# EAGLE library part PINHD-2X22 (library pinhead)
PIN HEADER

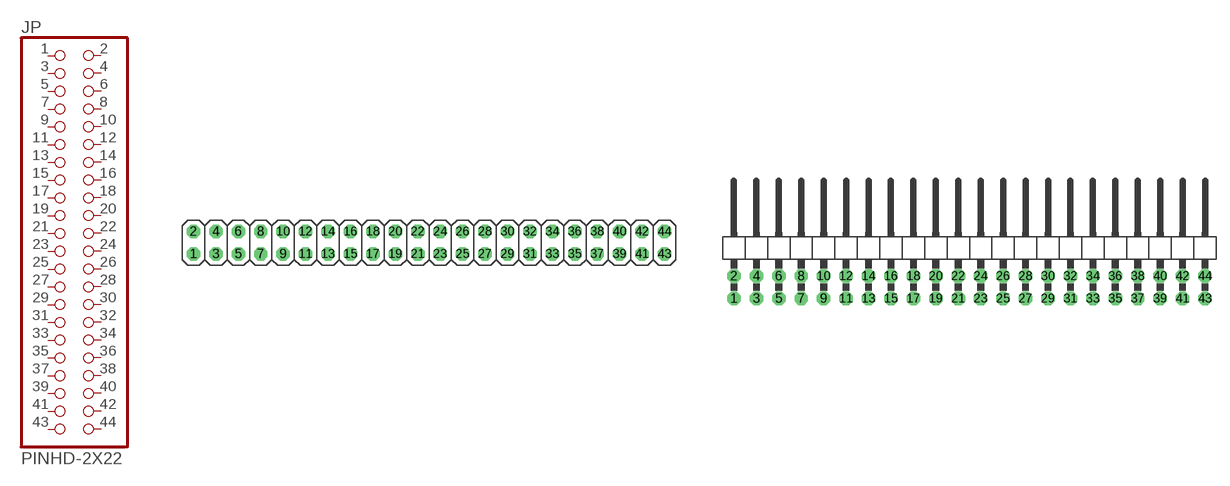
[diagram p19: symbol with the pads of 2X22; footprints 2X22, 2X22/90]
Designator prefix JP

## PINHD-2X22  [2X22]
1  1  pas
2  2  pas
3  3  pas
4  4  pas
5  5  pas
6  6  pas
7  7  pas
8  8  pas
9  9  pas
10  10  pas
11  11  pas
12  12  pas
13  13  pas
14  14  pas
15  15  pas
16  16  pas
17  17  pas
18  18  pas
19  19  pas
20  20  pas
21  21  pas
22  22  pas
23  23  pas
24  24  pas
25  25  pas
26  26  pas
27  27  pas
28  28  pas
29  29  pas
30  30  pas
31  31  pas
32  32  pas
33  33  pas
34  34  pas
35  35  pas
36  36  pas
37  37  pas
38  38  pas
39  39  pas
40  40  pas
41  41  pas
42  42  pas
43  43  pas
44  44  pas

## PINHD-2X22/90  [2X22/90]
1  1  pas
2  2  pas
3  3  pas
4  4  pas
5  5  pas
6  6  pas
7  7  pas
8  8  pas
9  9  pas
10  10  pas
11  11  pas
12  12  pas
13  13  pas
14  14  pas
15  15  pas
16  16  pas
17  17  pas
18  18  pas
19  19  pas
20  20  pas
21  21  pas
22  22  pas
23  23  pas
24  24  pas
25  25  pas
26  26  pas
27  27  pas
28  28  pas
29  29  pas
30  30  pas
31  31  pas
32  32  pas
33  33  pas
34  34  pas
35  35  pas
36  36  pas
37  37  pas
38  38  pas
39  39  pas
40  40  pas
41  42  pas
42  41  pas
43  44  pas
44  43  pas

## Footprint 2X22 (pad centres in mm)
PIN HEADER
drill 1.016 octagon: 1 -25.4,-1.27; 2 -25.4,1.27; 3 -22.86,-1.27; 4 -22.86,1.27; 5 -20.32,-1.27; 6 -20.32,1.27; 7 -17.78,-1.27; 8 -17.78,1.27; 9 -15.24,-1.27; 10 -15.24,1.27; 11 -12.7,-1.27; 12 -12.7,1.27; 13 -10.16,-1.27; 14 -10.16,1.27; 15 -7.62,-1.27; 16 -7.62,1.27; 17 -5.08,-1.27; 18 -5.08,1.27; 19 -2.54,-1.27; 20 -2.54,1.27; 21 0,-1.27; 22 0,1.27; 23 2.54,-1.27; 24 2.54,1.27; 25 5.08,-1.27; 26 5.08,1.27; 27 7.62,-1.27; 28 7.62,1.27; 29 10.16,-1.27; 30 10.16,1.27; 31 12.7,-1.27; 32 12.7,1.27; 33 15.24,-1.27; 34 15.24,1.27; 35 17.78,-1.27; 36 17.78,1.27; 37 20.32,-1.27; 38 20.32,1.27; 39 22.86,-1.27; 40 22.86,1.27; 41 25.4,-1.27; 42 25.4,1.27; 43 27.94,-1.27; 44 27.94,1.27

## Footprint 2X22/90 (pad centres in mm)
PIN HEADER
drill 1.016 octagon: 1 -26.67,-6.35; 2 -26.67,-3.81; 3 -24.13,-6.35; 4 -24.13,-3.81; 5 -21.59,-6.35; 6 -21.59,-3.81; 7 -19.05,-6.35; 8 -19.05,-3.81; 9 -16.51,-6.35; 10 -16.51,-3.81; 11 -13.97,-6.35; 12 -13.97,-3.81; 13 -11.43,-6.35; 14 -11.43,-3.81; 15 -8.89,-6.35; 16 -8.89,-3.81; 17 -6.35,-6.35; 18 -6.35,-3.81; 19 -3.81,-6.35; 20 -3.81,-3.81; 21 -1.27,-6.35; 22 -1.27,-3.81; 23 1.27,-6.35; 24 1.27,-3.81; 25 3.81,-6.35; 26 3.81,-3.81; 27 6.35,-6.35; 28 6.35,-3.81; 29 8.89,-6.35; 30 8.89,-3.81; 31 11.43,-6.35; 32 11.43,-3.81; 33 13.97,-6.35; 34 13.97,-3.81; 35 16.51,-6.35; 36 16.51,-3.81; 37 19.05,-6.35; 38 19.05,-3.81; 39 21.59,-6.35; 40 21.59,-3.81; 41 24.13,-6.35; 42 24.13,-3.81; 43 26.67,-6.35; 44 26.67,-3.81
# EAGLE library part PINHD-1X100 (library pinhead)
PIN HEADER 100 pol. Grid 2.54mm

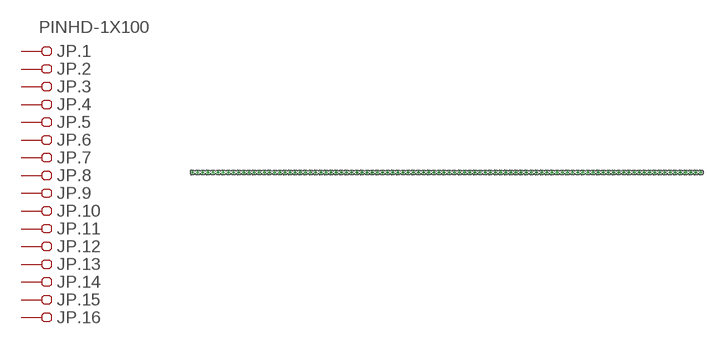
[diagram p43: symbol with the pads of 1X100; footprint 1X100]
Designator prefix JP; gates .1=PINHD_1V .2=PINHD_1 .3=PINHD_1 .4=PINHD_1 .5=PINHD_1 .6=PINHD_1 .7=PINHD_1 .8=PINHD_1 .9=PINHD_1 .10=PINHD_1 .11=PINHD_1 .12=PINHD_1 .13=PINHD_1 .14=PINHD_1 .15=PINHD_1 .16=PINHD_1 .17=PINHD_1 .18=PINHD_1 .19=PINHD_1 .20=PINHD_1 .21=PINHD_1 .22=PINHD_1 .23=PINHD_1 .24=PINHD_1 .25=PINHD_1 .26=PINHD_1 .27=PINHD_1 .28=PINHD_1 .29=PINHD_1 .30=PINHD_1 .31=PINHD_1 .32=PINHD_1 .33=PINHD_1 .34=PINHD_1 .35=PINHD_1 .36=PINHD_1 .37=PINHD_1 .38=PINHD_1 .39=PINHD_1 .40=PINHD_1 .41=PINHD_1 .42=PINHD_1 .43=PINHD_1 .44=PINHD_1 .45=PINHD_1 .46=PINHD_1 .47=PINHD_1 .48=PINHD_1 .49=PINHD_1 .50=PINHD_1 .51=PINHD_1 .52=PINHD_1 .53=PINHD_1 .54=PINHD_1 .55=PINHD_1 .56=PINHD_1 .57=PINHD_1 .58=PINHD_1 .59=PINHD_1 .60=PINHD_1 .61=PINHD_1 .62=PINHD_1 .63=PINHD_1 .64=PINHD_1 .65=PINHD_1 .66=PINHD_1 .67=PINHD_1 .68=PINHD_1 .69=PINHD_1 .70=PINHD_1 .71=PINHD_1 .72=PINHD_1 .73=PINHD_1 .74=PINHD_1 .75=PINHD_1 .76=PINHD_1 .77=PINHD_1 .78=PINHD_1 .79=PINHD_1 .80=PINHD_1 .81=PINHD_1 .82=PINHD_1 .83=PINHD_1 .84=PINHD_1 .85=PINHD_1 .86=PINHD_1 .87=PINHD_1 .88=PINHD_1 .89=PINHD_1 .90=PINHD_1 .91=PINHD_1 .92=PINHD_1 .93=PINHD_1 .94=PINHD_1 .95=PINHD_1 .96=PINHD_1 .97=PINHD_1 .98=PINHD_1 .99=PINHD_1 .100=PINHD_1

## PINHD-1X100  [1X100]
1  .1:1  pas
2  .2:1  pas
3  .3:1  pas
4  .4:1  pas
5  .5:1  pas
6  .6:1  pas
7  .7:1  pas
8  .8:1  pas
9  .9:1  pas
10  .10:1  pas
11  .11:1  pas
12  .12:1  pas
13  .13:1  pas
14  .14:1  pas
15  .15:1  pas
16  .16:1  pas
17  .17:1  pas
18  .18:1  pas
19  .19:1  pas
20  .20:1  pas
21  .21:1  pas
22  .22:1  pas
23  .23:1  pas
24  .24:1  pas
25  .25:1  pas
26  .26:1  pas
27  .27:1  pas
28  .28:1  pas
29  .29:1  pas
30  .30:1  pas
31  .31:1  pas
32  .32:1  pas
33  .33:1  pas
34  .34:1  pas
35  .35:1  pas
36  .36:1  pas
37  .37:1  pas
38  .38:1  pas
39  .39:1  pas
40  .40:1  pas
41  .41:1  pas
42  .42:1  pas
43  .43:1  pas
44  .44:1  pas
45  .45:1  pas
46  .46:1  pas
47  .47:1  pas
48  .48:1  pas
49  .49:1  pas
50  .50:1  pas
51  .51:1  pas
52  .52:1  pas
53  .53:1  pas
54  .54:1  pas
55  .55:1  pas
56  .56:1  pas
57  .57:1  pas
58  .58:1  pas
59  .59:1  pas
60  .60:1  pas
61  .61:1  pas
62  .62:1  pas
63  .63:1  pas
64  .64:1  pas
65  .65:1  pas
66  .66:1  pas
67  .67:1  pas
68  .68:1  pas
69  .69:1  pas
70  .70:1  pas
71  .71:1  pas
72  .72:1  pas
73  .73:1  pas
74  .74:1  pas
75  .75:1  pas
76  .76:1  pas
77  .77:1  pas
78  .78:1  pas
79  .79:1  pas
80  .80:1  pas
81  .81:1  pas
82  .82:1  pas
83  .83:1  pas
84  .84:1  pas
85  .85:1  pas
86  .86:1  pas
87  .87:1  pas
88  .88:1  pas
89  .89:1  pas
90  .90:1  pas
91  .91:1  pas
92  .92:1  pas
93  .93:1  pas
94  .94:1  pas
95  .95:1  pas
96  .96:1  pas
97  .97:1  pas
98  .98:1  pas
99  .99:1  pas
100  .100:1  pas

## Footprint 1X100 (pad centres in mm)
PIN HEADER 100 pol. Grid 2.54mm
drill 1.016: 1 -125.73,0; 2 -123.19,0; 3 -120.65,0; 4 -118.11,0; 5 -115.57,0; 6 -113.03,0; 7 -110.49,0; 8 -107.95,0; 9 -105.41,0; 10 -102.87,0; 11 -100.33,0; 12 -97.79,0; 13 -95.25,0; 14 -92.71,0; 15 -90.17,0; 16 -87.63,0; 17 -85.09,0; 18 -82.55,0; 19 -80.01,0; 20 -77.47,0; 21 -74.93,0; 22 -72.39,0; 23 -69.85,0; 24 -67.31,0; 25 -64.77,0; 26 -62.23,0; 27 -59.69,0; 28 -57.15,0; 29 -54.61,0; 30 -52.07,0; 31 -49.53,0; 32 -46.99,0; 33 -44.45,0; 34 -41.91,0; 35 -39.37,0; 36 -36.83,0; 37 -34.29,0; 38 -31.75,0; 39 -29.21,0; 40 -26.67,0; 41 -24.13,0; 42 -21.59,0; 43 -19.05,0; 44 -16.51,0; 45 -13.97,0; 46 -11.43,0; 47 -8.89,0; 48 -6.35,0; 49 -3.81,0; 50 -1.27,0; 51 1.27,0; 52 3.81,0; 53 6.35,0; 54 8.89,0; 55 11.43,0; 56 13.97,0; 57 16.51,0; 58 19.05,0; 59 21.59,0; 60 24.13,0; 61 26.67,0; 62 29.21,0; 63 31.75,0; 64 34.29,0; 65 36.83,0; 66 39.37,0; 67 41.91,0; 68 44.45,0; 69 46.99,0; 70 49.53,0; 71 52.07,0; 72 54.61,0; 73 57.15,0; 74 59.69,0; 75 62.23,0; 76 64.77,0; 77 67.31,0; 78 69.85,0; 79 72.39,0; 80 74.93,0; 81 77.47,0; 82 80.01,0; 83 82.55,0; 84 85.09,0; 85 87.63,0; 86 90.17,0; 87 92.71,0; 88 95.25,0; 89 97.79,0; 90 100.33,0; 91 102.87,0; 92 105.41,0; 93 107.95,0; 94 110.49,0; 95 113.03,0; 96 115.57,0; 97 118.11,0; 98 120.65,0; 99 123.19,0; 100 125.73,0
